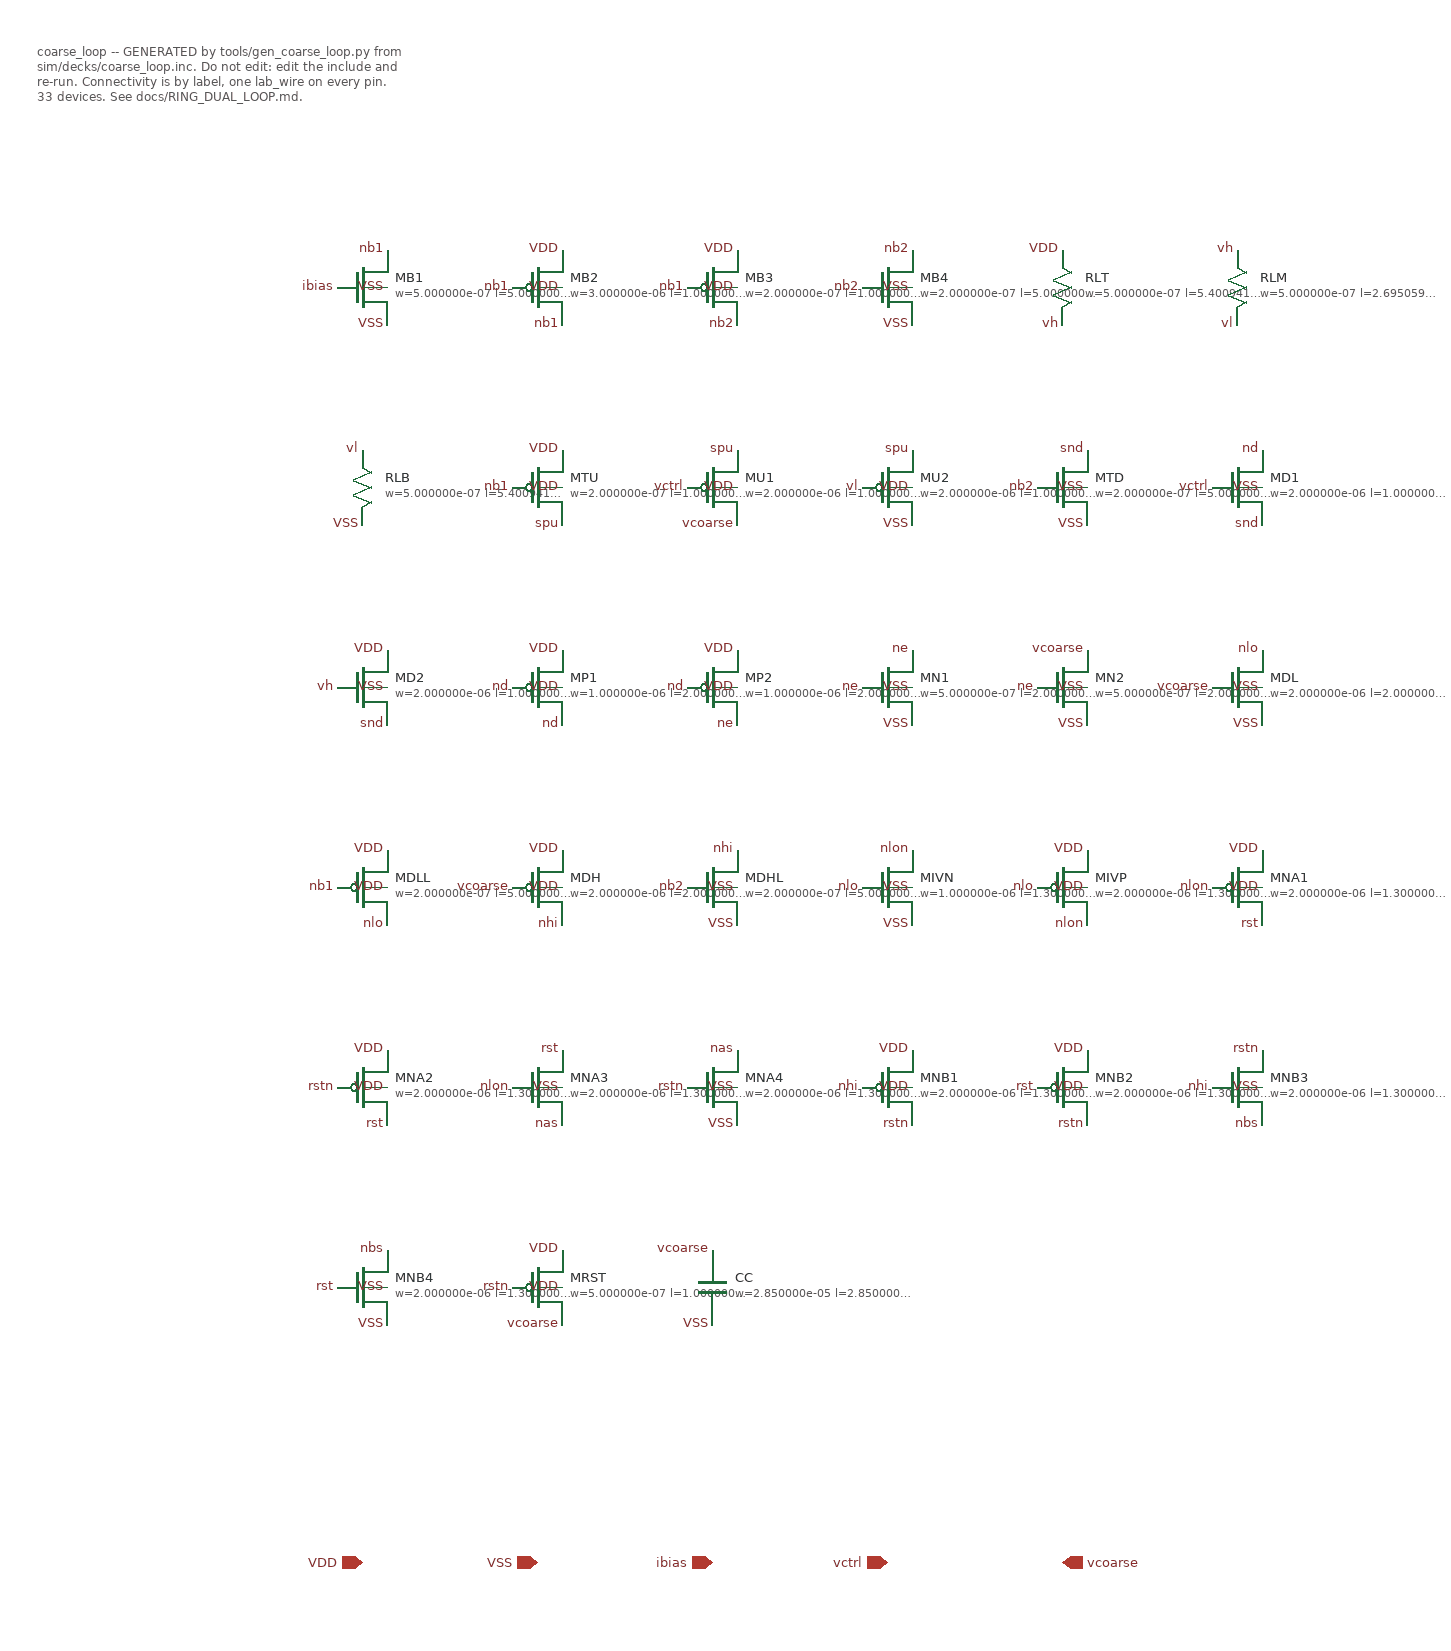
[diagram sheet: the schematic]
v {xschem version=3.4.5 file_version=1.2
}
G {}
K {}
V {}
S {}
E {}
T {coarse_loop -- GENERATED by tools/gen_coarse_loop.py from
sim/decks/coarse_loop.inc.  Do not edit: edit the include and
re-run.  Connectivity is by label, one lab_wire on every pin.
33 devices.  See docs/RING_DUAL_LOOP.md.} -260 -200 0 0 0.3 0.3 {}
C {sg13cmos5l_pr/sg13_lv_nmos.sym} 0 0 0 0 {name=MB1
l=5.000000e-06
w=5.000000e-07
ng=1
m=1
model=sg13_lv_nmos
mm_ok=1
spiceprefix=X}
C {devices/lab_wire.sym} 20 -30 0 0 {name=MB1_D sig_type=std_logic lab=nb1}
C {devices/lab_wire.sym} -20 0 0 0 {name=MB1_G sig_type=std_logic lab=ibias}
C {devices/lab_wire.sym} 20 30 0 0 {name=MB1_S sig_type=std_logic lab=VSS}
C {devices/lab_wire.sym} 20 0 0 0 {name=MB1_B sig_type=std_logic lab=VSS}
C {sg13cmos5l_pr/sg13_lv_pmos.sym} 140 0 0 0 {name=MB2
l=1.000000e-06
w=3.000000e-06
ng=1
m=1
model=sg13_lv_pmos
mm_ok=1
spiceprefix=X}
C {devices/lab_wire.sym} 160 30 0 0 {name=MB2_D sig_type=std_logic lab=nb1}
C {devices/lab_wire.sym} 120 0 0 0 {name=MB2_G sig_type=std_logic lab=nb1}
C {devices/lab_wire.sym} 160 -30 0 0 {name=MB2_S sig_type=std_logic lab=VDD}
C {devices/lab_wire.sym} 160 0 0 0 {name=MB2_B sig_type=std_logic lab=VDD}
C {sg13cmos5l_pr/sg13_lv_pmos.sym} 280 0 0 0 {name=MB3
l=1.000000e-05
w=2.000000e-07
ng=1
m=1
model=sg13_lv_pmos
mm_ok=1
spiceprefix=X}
C {devices/lab_wire.sym} 300 30 0 0 {name=MB3_D sig_type=std_logic lab=nb2}
C {devices/lab_wire.sym} 260 0 0 0 {name=MB3_G sig_type=std_logic lab=nb1}
C {devices/lab_wire.sym} 300 -30 0 0 {name=MB3_S sig_type=std_logic lab=VDD}
C {devices/lab_wire.sym} 300 0 0 0 {name=MB3_B sig_type=std_logic lab=VDD}
C {sg13cmos5l_pr/sg13_lv_nmos.sym} 420 0 0 0 {name=MB4
l=5.000000e-06
w=2.000000e-07
ng=1
m=1
model=sg13_lv_nmos
mm_ok=1
spiceprefix=X}
C {devices/lab_wire.sym} 440 -30 0 0 {name=MB4_D sig_type=std_logic lab=nb2}
C {devices/lab_wire.sym} 400 0 0 0 {name=MB4_G sig_type=std_logic lab=nb2}
C {devices/lab_wire.sym} 440 30 0 0 {name=MB4_S sig_type=std_logic lab=VSS}
C {devices/lab_wire.sym} 440 0 0 0 {name=MB4_B sig_type=std_logic lab=VSS}
C {sg13cmos5l_pr/rhigh.sym} 560 0 0 0 {name=RLT
l=5.400941e-05
w=5.000000e-07
m=1
b=0
body=sub!
model=rhigh
mm_ok=1
spiceprefix=X}
C {devices/lab_wire.sym} 560 -30 0 0 {name=RLT_P sig_type=std_logic lab=VDD}
C {devices/lab_wire.sym} 560 30 0 0 {name=RLT_M sig_type=std_logic lab=vh}
C {sg13cmos5l_pr/rhigh.sym} 700 0 0 0 {name=RLM
l=2.695059e-05
w=5.000000e-07
m=1
b=0
body=sub!
model=rhigh
mm_ok=1
spiceprefix=X}
C {devices/lab_wire.sym} 700 -30 0 0 {name=RLM_P sig_type=std_logic lab=vh}
C {devices/lab_wire.sym} 700 30 0 0 {name=RLM_M sig_type=std_logic lab=vl}
C {sg13cmos5l_pr/rhigh.sym} 0 160 0 0 {name=RLB
l=5.400941e-05
w=5.000000e-07
m=1
b=0
body=sub!
model=rhigh
mm_ok=1
spiceprefix=X}
C {devices/lab_wire.sym} 0 130 0 0 {name=RLB_P sig_type=std_logic lab=vl}
C {devices/lab_wire.sym} 0 190 0 0 {name=RLB_M sig_type=std_logic lab=VSS}
C {sg13cmos5l_pr/sg13_lv_pmos.sym} 140 160 0 0 {name=MTU
l=1.000000e-05
w=2.000000e-07
ng=1
m=1
model=sg13_lv_pmos
mm_ok=1
spiceprefix=X}
C {devices/lab_wire.sym} 160 190 0 0 {name=MTU_D sig_type=std_logic lab=spu}
C {devices/lab_wire.sym} 120 160 0 0 {name=MTU_G sig_type=std_logic lab=nb1}
C {devices/lab_wire.sym} 160 130 0 0 {name=MTU_S sig_type=std_logic lab=VDD}
C {devices/lab_wire.sym} 160 160 0 0 {name=MTU_B sig_type=std_logic lab=VDD}
C {sg13cmos5l_pr/sg13_lv_pmos.sym} 280 160 0 0 {name=MU1
l=1.000000e-06
w=2.000000e-06
ng=1
m=1
model=sg13_lv_pmos
mm_ok=1
spiceprefix=X}
C {devices/lab_wire.sym} 300 190 0 0 {name=MU1_D sig_type=std_logic lab=vcoarse}
C {devices/lab_wire.sym} 260 160 0 0 {name=MU1_G sig_type=std_logic lab=vctrl}
C {devices/lab_wire.sym} 300 130 0 0 {name=MU1_S sig_type=std_logic lab=spu}
C {devices/lab_wire.sym} 300 160 0 0 {name=MU1_B sig_type=std_logic lab=VDD}
C {sg13cmos5l_pr/sg13_lv_pmos.sym} 420 160 0 0 {name=MU2
l=1.000000e-06
w=2.000000e-06
ng=1
m=1
model=sg13_lv_pmos
mm_ok=1
spiceprefix=X}
C {devices/lab_wire.sym} 440 190 0 0 {name=MU2_D sig_type=std_logic lab=VSS}
C {devices/lab_wire.sym} 400 160 0 0 {name=MU2_G sig_type=std_logic lab=vl}
C {devices/lab_wire.sym} 440 130 0 0 {name=MU2_S sig_type=std_logic lab=spu}
C {devices/lab_wire.sym} 440 160 0 0 {name=MU2_B sig_type=std_logic lab=VDD}
C {sg13cmos5l_pr/sg13_lv_nmos.sym} 560 160 0 0 {name=MTD
l=5.000000e-06
w=2.000000e-07
ng=1
m=1
model=sg13_lv_nmos
mm_ok=1
spiceprefix=X}
C {devices/lab_wire.sym} 580 130 0 0 {name=MTD_D sig_type=std_logic lab=snd}
C {devices/lab_wire.sym} 540 160 0 0 {name=MTD_G sig_type=std_logic lab=nb2}
C {devices/lab_wire.sym} 580 190 0 0 {name=MTD_S sig_type=std_logic lab=VSS}
C {devices/lab_wire.sym} 580 160 0 0 {name=MTD_B sig_type=std_logic lab=VSS}
C {sg13cmos5l_pr/sg13_lv_nmos.sym} 700 160 0 0 {name=MD1
l=1.000000e-06
w=2.000000e-06
ng=1
m=1
model=sg13_lv_nmos
mm_ok=1
spiceprefix=X}
C {devices/lab_wire.sym} 720 130 0 0 {name=MD1_D sig_type=std_logic lab=nd}
C {devices/lab_wire.sym} 680 160 0 0 {name=MD1_G sig_type=std_logic lab=vctrl}
C {devices/lab_wire.sym} 720 190 0 0 {name=MD1_S sig_type=std_logic lab=snd}
C {devices/lab_wire.sym} 720 160 0 0 {name=MD1_B sig_type=std_logic lab=VSS}
C {sg13cmos5l_pr/sg13_lv_nmos.sym} 0 320 0 0 {name=MD2
l=1.000000e-06
w=2.000000e-06
ng=1
m=1
model=sg13_lv_nmos
mm_ok=1
spiceprefix=X}
C {devices/lab_wire.sym} 20 290 0 0 {name=MD2_D sig_type=std_logic lab=VDD}
C {devices/lab_wire.sym} -20 320 0 0 {name=MD2_G sig_type=std_logic lab=vh}
C {devices/lab_wire.sym} 20 350 0 0 {name=MD2_S sig_type=std_logic lab=snd}
C {devices/lab_wire.sym} 20 320 0 0 {name=MD2_B sig_type=std_logic lab=VSS}
C {sg13cmos5l_pr/sg13_lv_pmos.sym} 140 320 0 0 {name=MP1
l=2.000000e-06
w=1.000000e-06
ng=1
m=1
model=sg13_lv_pmos
mm_ok=1
spiceprefix=X}
C {devices/lab_wire.sym} 160 350 0 0 {name=MP1_D sig_type=std_logic lab=nd}
C {devices/lab_wire.sym} 120 320 0 0 {name=MP1_G sig_type=std_logic lab=nd}
C {devices/lab_wire.sym} 160 290 0 0 {name=MP1_S sig_type=std_logic lab=VDD}
C {devices/lab_wire.sym} 160 320 0 0 {name=MP1_B sig_type=std_logic lab=VDD}
C {sg13cmos5l_pr/sg13_lv_pmos.sym} 280 320 0 0 {name=MP2
l=2.000000e-06
w=1.000000e-06
ng=1
m=1
model=sg13_lv_pmos
mm_ok=1
spiceprefix=X}
C {devices/lab_wire.sym} 300 350 0 0 {name=MP2_D sig_type=std_logic lab=ne}
C {devices/lab_wire.sym} 260 320 0 0 {name=MP2_G sig_type=std_logic lab=nd}
C {devices/lab_wire.sym} 300 290 0 0 {name=MP2_S sig_type=std_logic lab=VDD}
C {devices/lab_wire.sym} 300 320 0 0 {name=MP2_B sig_type=std_logic lab=VDD}
C {sg13cmos5l_pr/sg13_lv_nmos.sym} 420 320 0 0 {name=MN1
l=2.000000e-06
w=5.000000e-07
ng=1
m=1
model=sg13_lv_nmos
mm_ok=1
spiceprefix=X}
C {devices/lab_wire.sym} 440 290 0 0 {name=MN1_D sig_type=std_logic lab=ne}
C {devices/lab_wire.sym} 400 320 0 0 {name=MN1_G sig_type=std_logic lab=ne}
C {devices/lab_wire.sym} 440 350 0 0 {name=MN1_S sig_type=std_logic lab=VSS}
C {devices/lab_wire.sym} 440 320 0 0 {name=MN1_B sig_type=std_logic lab=VSS}
C {sg13cmos5l_pr/sg13_lv_nmos.sym} 560 320 0 0 {name=MN2
l=2.000000e-06
w=5.000000e-07
ng=1
m=1
model=sg13_lv_nmos
mm_ok=1
spiceprefix=X}
C {devices/lab_wire.sym} 580 290 0 0 {name=MN2_D sig_type=std_logic lab=vcoarse}
C {devices/lab_wire.sym} 540 320 0 0 {name=MN2_G sig_type=std_logic lab=ne}
C {devices/lab_wire.sym} 580 350 0 0 {name=MN2_S sig_type=std_logic lab=VSS}
C {devices/lab_wire.sym} 580 320 0 0 {name=MN2_B sig_type=std_logic lab=VSS}
C {sg13cmos5l_pr/sg13_lv_nmos.sym} 700 320 0 0 {name=MDL
l=2.000000e-06
w=2.000000e-06
ng=1
m=1
model=sg13_lv_nmos
mm_ok=1
spiceprefix=X}
C {devices/lab_wire.sym} 720 290 0 0 {name=MDL_D sig_type=std_logic lab=nlo}
C {devices/lab_wire.sym} 680 320 0 0 {name=MDL_G sig_type=std_logic lab=vcoarse}
C {devices/lab_wire.sym} 720 350 0 0 {name=MDL_S sig_type=std_logic lab=VSS}
C {devices/lab_wire.sym} 720 320 0 0 {name=MDL_B sig_type=std_logic lab=VSS}
C {sg13cmos5l_pr/sg13_lv_pmos.sym} 0 480 0 0 {name=MDLL
l=5.000000e-06
w=2.000000e-07
ng=1
m=1
model=sg13_lv_pmos
mm_ok=1
spiceprefix=X}
C {devices/lab_wire.sym} 20 510 0 0 {name=MDLL_D sig_type=std_logic lab=nlo}
C {devices/lab_wire.sym} -20 480 0 0 {name=MDLL_G sig_type=std_logic lab=nb1}
C {devices/lab_wire.sym} 20 450 0 0 {name=MDLL_S sig_type=std_logic lab=VDD}
C {devices/lab_wire.sym} 20 480 0 0 {name=MDLL_B sig_type=std_logic lab=VDD}
C {sg13cmos5l_pr/sg13_lv_pmos.sym} 140 480 0 0 {name=MDH
l=2.000000e-06
w=2.000000e-06
ng=1
m=1
model=sg13_lv_pmos
mm_ok=1
spiceprefix=X}
C {devices/lab_wire.sym} 160 510 0 0 {name=MDH_D sig_type=std_logic lab=nhi}
C {devices/lab_wire.sym} 120 480 0 0 {name=MDH_G sig_type=std_logic lab=vcoarse}
C {devices/lab_wire.sym} 160 450 0 0 {name=MDH_S sig_type=std_logic lab=VDD}
C {devices/lab_wire.sym} 160 480 0 0 {name=MDH_B sig_type=std_logic lab=VDD}
C {sg13cmos5l_pr/sg13_lv_nmos.sym} 280 480 0 0 {name=MDHL
l=5.000000e-06
w=2.000000e-07
ng=1
m=1
model=sg13_lv_nmos
mm_ok=1
spiceprefix=X}
C {devices/lab_wire.sym} 300 450 0 0 {name=MDHL_D sig_type=std_logic lab=nhi}
C {devices/lab_wire.sym} 260 480 0 0 {name=MDHL_G sig_type=std_logic lab=nb2}
C {devices/lab_wire.sym} 300 510 0 0 {name=MDHL_S sig_type=std_logic lab=VSS}
C {devices/lab_wire.sym} 300 480 0 0 {name=MDHL_B sig_type=std_logic lab=VSS}
C {sg13cmos5l_pr/sg13_lv_nmos.sym} 420 480 0 0 {name=MIVN
l=1.300000e-07
w=1.000000e-06
ng=1
m=1
model=sg13_lv_nmos
mm_ok=1
spiceprefix=X}
C {devices/lab_wire.sym} 440 450 0 0 {name=MIVN_D sig_type=std_logic lab=nlon}
C {devices/lab_wire.sym} 400 480 0 0 {name=MIVN_G sig_type=std_logic lab=nlo}
C {devices/lab_wire.sym} 440 510 0 0 {name=MIVN_S sig_type=std_logic lab=VSS}
C {devices/lab_wire.sym} 440 480 0 0 {name=MIVN_B sig_type=std_logic lab=VSS}
C {sg13cmos5l_pr/sg13_lv_pmos.sym} 560 480 0 0 {name=MIVP
l=1.300000e-07
w=2.000000e-06
ng=1
m=1
model=sg13_lv_pmos
mm_ok=1
spiceprefix=X}
C {devices/lab_wire.sym} 580 510 0 0 {name=MIVP_D sig_type=std_logic lab=nlon}
C {devices/lab_wire.sym} 540 480 0 0 {name=MIVP_G sig_type=std_logic lab=nlo}
C {devices/lab_wire.sym} 580 450 0 0 {name=MIVP_S sig_type=std_logic lab=VDD}
C {devices/lab_wire.sym} 580 480 0 0 {name=MIVP_B sig_type=std_logic lab=VDD}
C {sg13cmos5l_pr/sg13_lv_pmos.sym} 700 480 0 0 {name=MNA1
l=1.300000e-07
w=2.000000e-06
ng=1
m=1
model=sg13_lv_pmos
mm_ok=1
spiceprefix=X}
C {devices/lab_wire.sym} 720 510 0 0 {name=MNA1_D sig_type=std_logic lab=rst}
C {devices/lab_wire.sym} 680 480 0 0 {name=MNA1_G sig_type=std_logic lab=nlon}
C {devices/lab_wire.sym} 720 450 0 0 {name=MNA1_S sig_type=std_logic lab=VDD}
C {devices/lab_wire.sym} 720 480 0 0 {name=MNA1_B sig_type=std_logic lab=VDD}
C {sg13cmos5l_pr/sg13_lv_pmos.sym} 0 640 0 0 {name=MNA2
l=1.300000e-07
w=2.000000e-06
ng=1
m=1
model=sg13_lv_pmos
mm_ok=1
spiceprefix=X}
C {devices/lab_wire.sym} 20 670 0 0 {name=MNA2_D sig_type=std_logic lab=rst}
C {devices/lab_wire.sym} -20 640 0 0 {name=MNA2_G sig_type=std_logic lab=rstn}
C {devices/lab_wire.sym} 20 610 0 0 {name=MNA2_S sig_type=std_logic lab=VDD}
C {devices/lab_wire.sym} 20 640 0 0 {name=MNA2_B sig_type=std_logic lab=VDD}
C {sg13cmos5l_pr/sg13_lv_nmos.sym} 140 640 0 0 {name=MNA3
l=1.300000e-07
w=2.000000e-06
ng=1
m=1
model=sg13_lv_nmos
mm_ok=1
spiceprefix=X}
C {devices/lab_wire.sym} 160 610 0 0 {name=MNA3_D sig_type=std_logic lab=rst}
C {devices/lab_wire.sym} 120 640 0 0 {name=MNA3_G sig_type=std_logic lab=nlon}
C {devices/lab_wire.sym} 160 670 0 0 {name=MNA3_S sig_type=std_logic lab=nas}
C {devices/lab_wire.sym} 160 640 0 0 {name=MNA3_B sig_type=std_logic lab=VSS}
C {sg13cmos5l_pr/sg13_lv_nmos.sym} 280 640 0 0 {name=MNA4
l=1.300000e-07
w=2.000000e-06
ng=1
m=1
model=sg13_lv_nmos
mm_ok=1
spiceprefix=X}
C {devices/lab_wire.sym} 300 610 0 0 {name=MNA4_D sig_type=std_logic lab=nas}
C {devices/lab_wire.sym} 260 640 0 0 {name=MNA4_G sig_type=std_logic lab=rstn}
C {devices/lab_wire.sym} 300 670 0 0 {name=MNA4_S sig_type=std_logic lab=VSS}
C {devices/lab_wire.sym} 300 640 0 0 {name=MNA4_B sig_type=std_logic lab=VSS}
C {sg13cmos5l_pr/sg13_lv_pmos.sym} 420 640 0 0 {name=MNB1
l=1.300000e-07
w=2.000000e-06
ng=1
m=1
model=sg13_lv_pmos
mm_ok=1
spiceprefix=X}
C {devices/lab_wire.sym} 440 670 0 0 {name=MNB1_D sig_type=std_logic lab=rstn}
C {devices/lab_wire.sym} 400 640 0 0 {name=MNB1_G sig_type=std_logic lab=nhi}
C {devices/lab_wire.sym} 440 610 0 0 {name=MNB1_S sig_type=std_logic lab=VDD}
C {devices/lab_wire.sym} 440 640 0 0 {name=MNB1_B sig_type=std_logic lab=VDD}
C {sg13cmos5l_pr/sg13_lv_pmos.sym} 560 640 0 0 {name=MNB2
l=1.300000e-07
w=2.000000e-06
ng=1
m=1
model=sg13_lv_pmos
mm_ok=1
spiceprefix=X}
C {devices/lab_wire.sym} 580 670 0 0 {name=MNB2_D sig_type=std_logic lab=rstn}
C {devices/lab_wire.sym} 540 640 0 0 {name=MNB2_G sig_type=std_logic lab=rst}
C {devices/lab_wire.sym} 580 610 0 0 {name=MNB2_S sig_type=std_logic lab=VDD}
C {devices/lab_wire.sym} 580 640 0 0 {name=MNB2_B sig_type=std_logic lab=VDD}
C {sg13cmos5l_pr/sg13_lv_nmos.sym} 700 640 0 0 {name=MNB3
l=1.300000e-07
w=2.000000e-06
ng=1
m=1
model=sg13_lv_nmos
mm_ok=1
spiceprefix=X}
C {devices/lab_wire.sym} 720 610 0 0 {name=MNB3_D sig_type=std_logic lab=rstn}
C {devices/lab_wire.sym} 680 640 0 0 {name=MNB3_G sig_type=std_logic lab=nhi}
C {devices/lab_wire.sym} 720 670 0 0 {name=MNB3_S sig_type=std_logic lab=nbs}
C {devices/lab_wire.sym} 720 640 0 0 {name=MNB3_B sig_type=std_logic lab=VSS}
C {sg13cmos5l_pr/sg13_lv_nmos.sym} 0 800 0 0 {name=MNB4
l=1.300000e-07
w=2.000000e-06
ng=1
m=1
model=sg13_lv_nmos
mm_ok=1
spiceprefix=X}
C {devices/lab_wire.sym} 20 770 0 0 {name=MNB4_D sig_type=std_logic lab=nbs}
C {devices/lab_wire.sym} -20 800 0 0 {name=MNB4_G sig_type=std_logic lab=rst}
C {devices/lab_wire.sym} 20 830 0 0 {name=MNB4_S sig_type=std_logic lab=VSS}
C {devices/lab_wire.sym} 20 800 0 0 {name=MNB4_B sig_type=std_logic lab=VSS}
C {sg13cmos5l_pr/sg13_lv_pmos.sym} 140 800 0 0 {name=MRST
l=1.000000e-06
w=5.000000e-07
ng=1
m=1
model=sg13_lv_pmos
mm_ok=1
spiceprefix=X}
C {devices/lab_wire.sym} 160 830 0 0 {name=MRST_D sig_type=std_logic lab=vcoarse}
C {devices/lab_wire.sym} 120 800 0 0 {name=MRST_G sig_type=std_logic lab=rstn}
C {devices/lab_wire.sym} 160 770 0 0 {name=MRST_S sig_type=std_logic lab=VDD}
C {devices/lab_wire.sym} 160 800 0 0 {name=MRST_B sig_type=std_logic lab=VDD}
C {sg13cmos5l_pr/cap_cmomf.sym} 280 800 0 0 {name=CC
l=2.850000e-05
w=2.850000e-05
m=1
mmin=1
mmax=4
subblock=0
model=cap_cmomf
mm_ok=1
spiceprefix=X}
C {devices/lab_wire.sym} 280 770 0 0 {name=CC_c0 sig_type=std_logic lab=vcoarse}
C {devices/lab_wire.sym} 280 830 0 0 {name=CC_c1 sig_type=std_logic lab=VSS}
C {devices/iopin.sym} 0 1020 0 0 {name=P0 lab=VDD}
C {devices/iopin.sym} 140 1020 0 0 {name=P1 lab=VSS}
C {devices/ipin.sym} 280 1020 0 0 {name=P2 lab=ibias}
C {devices/ipin.sym} 420 1020 0 0 {name=P3 lab=vctrl}
C {devices/opin.sym} 560 1020 0 0 {name=P4 lab=vcoarse}
